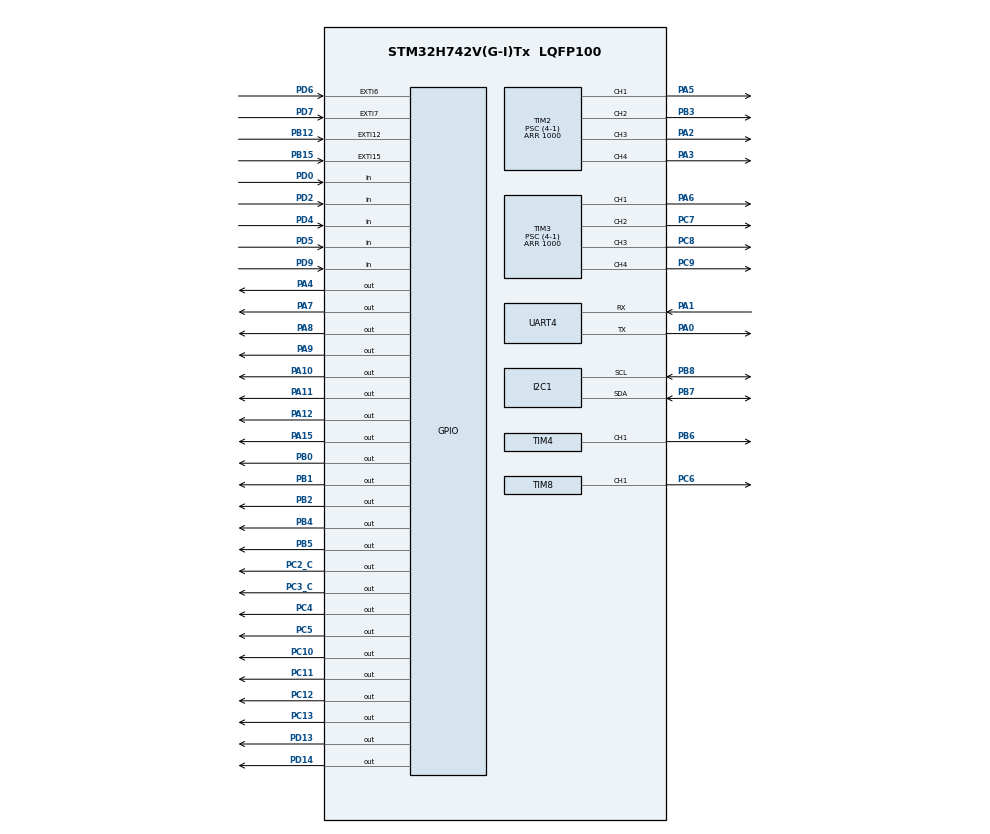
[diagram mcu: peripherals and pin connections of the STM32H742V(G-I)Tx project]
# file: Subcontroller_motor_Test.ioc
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I2C1.Timing=0x109093DC
Mcu.Family=STM32H7
Mcu.Name=STM32H742V(G-I)Tx
Mcu.Package=LQFP100
NVIC.EXTI15_10_IRQn=true\:0\:0\:false\:false\:true\:true\:true\:true
NVIC.EXTI9_5_IRQn=true\:0\:0\:false\:false\:true\:true\:true\:true
NVIC.PriorityGroup=NVIC_PRIORITYGROUP_4
NVIC.TIM2_IRQn=true\:0\:0\:false\:false\:true\:true\:true\:true
NVIC.TIM3_IRQn=true\:0\:0\:false\:false\:true\:true\:true\:true
NVIC.TIM4_IRQn=true\:0\:0\:false\:false\:true\:true\:true\:true
NVIC.TIM7_IRQn=true\:0\:0\:false\:false\:true\:true\:true\:true
NVIC.TIM8_BRK_TIM12_IRQn=true\:0\:0\:false\:false\:true\:true\:true\:true
NVIC.TIM8_CC_IRQn=true\:0\:0\:false\:false\:true\:true\:true\:true
NVIC.TIM8_TRG_COM_TIM14_IRQn=true\:0\:0\:false\:false\:true\:true\:true\:true
NVIC.TIM8_UP_TIM13_IRQn=true\:0\:0\:false\:false\:true\:true\:true\:true
NVIC.UART4_IRQn=true\:0\:0\:false\:false\:true\:true\:true\:true
PA0.Mode=Asynchronous
PA0.Signal=UART4_TX
PA1.Mode=Asynchronous
PA1.Signal=UART4_RX
PA10.PinState=GPIO_PIN_SET
PA10.Signal=GPIO_Output
PA11.PinState=GPIO_PIN_SET
PA11.Signal=GPIO_Output
PA12.PinState=GPIO_PIN_SET
PA12.Signal=GPIO_Output
PA15\ (JTDI).PinState=GPIO_PIN_SET
PA15\ (JTDI).Signal=GPIO_Output
PA2.Signal=S_TIM2_CH3
PA3.Signal=S_TIM2_CH4
PA4.PinState=GPIO_PIN_RESET
PA4.Signal=GPIO_Output
PA5.Signal=S_TIM2_CH1_ETR
PA6.Signal=S_TIM3_CH1
PA7.PinState=GPIO_PIN_RESET
PA7.Signal=GPIO_Output
PA8.PinState=GPIO_PIN_RESET
PA8.Signal=GPIO_Output
PA9.PinState=GPIO_PIN_SET
PA9.Signal=GPIO_Output
PB0.Signal=GPIO_Output
PB1.PinState=GPIO_PIN_SET
PB1.Signal=GPIO_Output
PB12.GPIO_ModeDefaultEXTI=GPIO_MODE_IT_FALLING
PB12.Signal=GPXTI12
PB15.Signal=GPXTI15
PB2.PinState=GPIO_PIN_SET
PB2.Signal=GPIO_Output
PB3\ (JTDO/TRACESWO).Signal=S_TIM2_CH2
PB4\ (NJTRST).PinState=GPIO_PIN_RESET
PB4\ (NJTRST).Signal=GPIO_Output
PB5.PinState=GPIO_PIN_SET
PB5.Signal=GPIO_Output
PB6.Signal=S_TIM4_CH1
PB7.Mode=I2C
PB7.Signal=I2C1_SDA
PB8.Mode=I2C
PB8.Signal=I2C1_SCL
PC10.PinState=GPIO_PIN_RESET
PC10.Signal=GPIO_Output
PC11.PinState=GPIO_PIN_SET
PC11.Signal=GPIO_Output
PC12.PinState=GPIO_PIN_RESET
PC12.Signal=GPIO_Output
PC13.PinState=GPIO_PIN_SET
PC13.Signal=GPIO_Output
PC2_C.PinState=GPIO_PIN_SET
PC2_C.Signal=GPIO_Output
PC3_C.PinState=GPIO_PIN_RESET
PC3_C.Signal=GPIO_Output
PC4.PinState=GPIO_PIN_SET
PC4.Signal=GPIO_Output
PC5.PinState=GPIO_PIN_SET
PC5.Signal=GPIO_Output
PC6.Signal=S_TIM8_CH1
PC7.Signal=S_TIM3_CH2
PC8.Signal=S_TIM3_CH3
PC9.Signal=S_TIM3_CH4
PD0.Signal=GPIO_Input
PD13.PinState=GPIO_PIN_RESET
PD13.Signal=GPIO_Output
PD14.PinState=GPIO_PIN_RESET
PD14.Signal=GPIO_Output
PD2.Signal=GPIO_Input
PD4.Signal=GPIO_Input
PD5.Signal=GPIO_Input
PD6.GPIO_ModeDefaultEXTI=GPIO_MODE_IT_FALLING
PD6.Signal=GPXTI6
PD7.GPIO_ModeDefaultEXTI=GPIO_MODE_IT_FALLING
PD7.Signal=GPXTI7
PD9.Signal=GPIO_Input
ProjectManager.HeapSize=0x200
ProjectManager.StackSize=0x400
ProjectManager.TargetToolchain=STM32CubeIDE
RCC.ADCFreq_Value=129000000
RCC.APB1Freq_Value=75000000
RCC.APB2Freq_Value=75000000
RCC.APB3Freq_Value=75000000
RCC.APB4Freq_Value=75000000
RCC.CortexFreq_Value=300000000
RCC.D1PPRE=RCC_APB3_DIV2
RCC.D2PPRE1=RCC_APB1_DIV2
RCC.D2PPRE2=RCC_APB2_DIV2
RCC.D3PPRE=RCC_APB4_DIV2
RCC.DIVM1=8
RCC.DIVN1=75
RCC.HCLKFreq_Value=150000000
RCC.HPRE=RCC_HCLK_DIV2
RCC.PLL1_VCI_Range-AdvancedSettings=RCC_PLL1VCIRANGE_0
RCC.PLL1_VCO_SEL-AdvancedSettings=RCC_PLL1VCOMEDIUM
RCC.PLL2_VCI_Range-AdvancedSettings=RCC_PLL2VCIRANGE_0
RCC.PLL2_VCO_SEL-AdvancedSettings=RCC_PLL2VCOWIDE
RCC.SYSCLKFreq_VALUE=300000000
RCC.SYSCLKSource=RCC_SYSCLKSOURCE_PLLCLK
RCC.USBFreq_Value=300000000
SH.S_TIM2_CH1_ETR.0=TIM2_CH1,PWM Generation1 CH1
SH.S_TIM2_CH2.0=TIM2_CH2,PWM Generation2 CH2
SH.S_TIM2_CH3.0=TIM2_CH3,PWM Generation3 CH3
SH.S_TIM2_CH4.0=TIM2_CH4,PWM Generation4 CH4
SH.S_TIM3_CH1.0=TIM3_CH1,PWM Generation1 CH1
SH.S_TIM3_CH2.0=TIM3_CH2,PWM Generation2 CH2
SH.S_TIM3_CH3.0=TIM3_CH3,PWM Generation3 CH3
SH.S_TIM3_CH4.0=TIM3_CH4,PWM Generation4 CH4
SH.S_TIM4_CH1.0=TIM4_CH1,PWM Generation1 CH1
SH.S_TIM8_CH1.0=TIM8_CH1,PWM Generation1 CH1
TIM2.Channel-PWM\ Generation1\ CH1=TIM_CHANNEL_1
TIM2.Channel-PWM\ Generation2\ CH2=TIM_CHANNEL_2
TIM2.Channel-PWM\ Generation3\ CH3=TIM_CHANNEL_3
TIM2.Channel-PWM\ Generation4\ CH4=TIM_CHANNEL_4
TIM2.Period=1000
TIM2.Prescaler=(4-1)
TIM2.Pulse-PWM\ Generation1\ CH1=500
TIM2.Pulse-PWM\ Generation2\ CH2=500
TIM2.Pulse-PWM\ Generation3\ CH3=500
TIM2.Pulse-PWM\ Generation4\ CH4=500
TIM3.Channel-PWM\ Generation1\ CH1=TIM_CHANNEL_1
TIM3.Channel-PWM\ Generation2\ CH2=TIM_CHANNEL_2
TIM3.Channel-PWM\ Generation3\ CH3=TIM_CHANNEL_3
TIM3.Channel-PWM\ Generation4\ CH4=TIM_CHANNEL_4
TIM3.Period=1000
TIM3.Prescaler=(4-1)
TIM3.Pulse-PWM\ Generation1\ CH1=500
TIM3.Pulse-PWM\ Generation2\ CH2=500
TIM3.Pulse-PWM\ Generation3\ CH3=500
TIM3.Pulse-PWM\ Generation4\ CH4=500
TIM4.Channel-PWM\ Generation1\ CH1=TIM_CHANNEL_1
TIM4.Period=650
TIM4.Prescaler=(4-1)
TIM4.Pulse-PWM\ Generation1\ CH1=325
TIM7.Period=50000
TIM7.Prescaler=3000
TIM8.Channel-PWM\ Generation1\ CH1=TIM_CHANNEL_1
TIM8.Period=1000
TIM8.Prescaler=(4-1)
TIM8.Pulse-PWM\ Generation1\ CH1=500
VP_TIM2_VS_ClockSourceINT.Mode=Internal
VP_TIM3_VS_ClockSourceINT.Mode=Internal
VP_TIM4_VS_ClockSourceINT.Mode=Internal
VP_TIM7_VS_ClockSourceINT.Mode=Enable_Timer
VP_TIM8_VS_ClockSourceINT.Mode=Internal
board=custom

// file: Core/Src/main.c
/* USER CODE BEGIN Header */
/**
  ******************************************************************************
  * @file           : main.c
  * @brief          : Main program body
  ******************************************************************************
  * @attention
  *
  * Copyright (c) 2022 STMicroelectronics.
  * All rights reserved.
  *
  * This software is licensed under terms that can be found in the LICENSE file
  * in the root directory of this software component.
  * If no LICENSE file comes with this software, it is provided AS-IS.
  *
  ******************************************************************************
  */
/* USER CODE END Header */
#include "main.h"

/* USER CODE BEGIN Includes */
#include <string.h>
#include "../Phoropter/Inc/common.h"

/* USER CODE END Includes */

/* USER CODE BEGIN PD */

private_var pv;

void  Initial_Homing();

/* USER CODE END PD */

I2C_HandleTypeDef hi2c1;
I2C_HandleTypeDef hi2c1;

TIM_HandleTypeDef htim2;
TIM_HandleTypeDef htim3;
TIM_HandleTypeDef htim4;
TIM_HandleTypeDef htim7;
TIM_HandleTypeDef htim8;

UART_HandleTypeDef huart4;

void SystemClock_Config(void);
static void MX_GPIO_Init(void);
static void MX_TIM3_Init(void);
static void MX_TIM8_Init(void);
static void MX_UART4_Init(void);
static void MX_TIM2_Init(void);
static void MX_TIM7_Init(void);
static void MX_TIM4_Init(void);
static void MX_I2C1_Init(void);

/* USER CODE BEGIN 0 */
uint32_t zCmdRx = 0;
/* USER CODE END 0 */

int main(void)
{
	/* USER CODE BEGIN 1 */
	uint32_t flash_magic_num;
	/* USER CODE END 1 */

	/* MCU Configuration--------------------------------------------------------*/

	/* Reset of all peripherals, Initializes the Flash interface and the Systick. */
	HAL_Init();

	/* Configure the system clock */
	SystemClock_Config();

	/* USER CODE BEGIN SysInit */
	/* Initialize the Private variable */
	Init_PV();

	/* USER CODE END SysInit */

	/* Initialize all configured peripherals */
	MX_GPIO_Init();
	MX_TIM3_Init();
	MX_TIM8_Init();
	MX_UART4_Init();
	MX_TIM2_Init();
	MX_TIM7_Init();
	MX_TIM4_Init();
	MX_I2C1_Init();

#if 1

	/* Read the value from the Flash Memory */
	memset(&pv.cal_disc[0], 0x00, sizeof(pv.cal_disc));
	Flash_Read_Data(FLASH_CONF_ADDR, (uint32_t *)&pv.cal_disc[0], 128/4);

	/* Check for the Magic number */
	flash_magic_num = pv.cal_disc[11];

	if (FLASH_MAGIC_NUMBER != flash_magic_num)
	{
		/* USER CODE BEGIN 2 */
		/* Write default calibration data into flash */
		pv.cal_disc[0]  =  2000;
		pv.cal_disc[1]  =  2000;
		pv.cal_disc[2]  =  2000;
		pv.cal_disc[3]  =  2000;
		pv.cal_disc[4]  =  2000;
		pv.cal_disc[5]  =  2000;
		pv.cal_disc[6]  =  0;
		pv.cal_disc[7]  =  180000;
		pv.cal_disc[8]  =  90;
		pv.cal_disc[9]  =  90;
		pv.cal_disc[10] =  0;
		pv.cal_disc[11] =  0x12345678;		//This Value for Left Side Flash Memory

		/* Write the data into the Flash config location */
		Flash_Write_Data(FLASH_CONF_ADDR, (uint32_t *)&pv.cal_disc[0], 128/4);
		HAL_Delay(100);
	}

#endif

	memset(&pv.cal_disc[0], 0x00, sizeof(pv.cal_disc));
	Flash_Read_Data(FLASH_CONF_ADDR, (uint32_t *)&pv.cal_disc[0], 128/4);

	/* enable update interrupt for timer */
	TIM3->DIER |=(1<<0);    //Disc 4 (TIM3_CH1) //Axis (TIM3_CH3)
	TIM8->DIER |=(1<<0);    //DISC 6 (TIM8_CH1)
	TIM4->DIER |=(1<<0);    //PD Motor
	TIM2->DIER |=(1<<0);    //Disc 5 (TIM2_CH2) //Disc 3 (TIM2_CH1) //Disc 1 (TIM2_CH3)
	//Disc 2 (TIM2_CH4)

	/* Trying to read the IO Expander Register */
	/*
	 * Homing position for Disc1 to Disc6, PD motor, DC motor
	 * Prism1 & Prism2 and Axis motor.
	 */

	//Init_IOExpander(&hi2c1);

	/* Set the Homing Position */
	Initial_Homing();

	pv.motor_error = MOTOR_SUCCESS;
	pv.hi2c1   = &hi2c1;

	/* Initialize the UART */
	/* Enable the interrupt for receiving the data from Main board module */
	memset(&pv.rx_buf[0], 0x00, sizeof(pv.rx_buf));
	HAL_UART_RegisterCallback(pv.huart4, HAL_UART_RX_COMPLETE_CB_ID, HAL_UART4_RxCpltCallback);
	HAL_UART_Receive_IT(pv.huart4,&pv.rx_buf[0],sizeof(pv.rx_buf));

	/* USER CODE END 2 */
	/* Infinite loop */
	/* USER CODE BEGIN WHILE */
	while(1)
	{
		/* Check the motor status and Send the status to the Main board */
		check_motor_status();

    	/* Call the Receive function */
    	MBCmdReceivefunc();

    	/* USER CODE END WHILE */

	}
}

void SystemClock_Config(void)
{
	RCC_OscInitTypeDef RCC_OscInitStruct = {0};
	RCC_ClkInitTypeDef RCC_ClkInitStruct = {0};

	/** Supply configuration update enable
	 */
	HAL_PWREx_ConfigSupply(PWR_LDO_SUPPLY);

	/** Configure the main internal regulator output voltage
	 */
	__HAL_PWR_VOLTAGESCALING_CONFIG(PWR_REGULATOR_VOLTAGE_SCALE2);

	while(!__HAL_PWR_GET_FLAG(PWR_FLAG_VOSRDY)) {}

	/** Initializes the RCC Oscillators according to the specified parameters
	 * in the RCC_OscInitTypeDef structure.
	 */
	RCC_OscInitStruct.OscillatorType = RCC_OSCILLATORTYPE_HSI;
	RCC_OscInitStruct.HSIState = RCC_HSI_DIV1;
	RCC_OscInitStruct.HSICalibrationValue = RCC_HSICALIBRATION_DEFAULT;
	RCC_OscInitStruct.PLL.PLLState = RCC_PLL_ON;
	RCC_OscInitStruct.PLL.PLLSource = RCC_PLLSOURCE_HSI;
	RCC_OscInitStruct.PLL.PLLM = 8;
	RCC_OscInitStruct.PLL.PLLN = 75;
	RCC_OscInitStruct.PLL.PLLP = 2;
	RCC_OscInitStruct.PLL.PLLQ = 2;
	RCC_OscInitStruct.PLL.PLLR = 2;
	RCC_OscInitStruct.PLL.PLLRGE = RCC_PLL1VCIRANGE_3;
	RCC_OscInitStruct.PLL.PLLVCOSEL = RCC_PLL1VCOWIDE;
	RCC_OscInitStruct.PLL.PLLFRACN = 0;
	if (HAL_RCC_OscConfig(&RCC_OscInitStruct) != HAL_OK)
	{
		Error_Handler();
	}

	/** Initializes the CPU, AHB and APB buses clocks
	 */
	RCC_ClkInitStruct.ClockType = RCC_CLOCKTYPE_HCLK|RCC_CLOCKTYPE_SYSCLK
                              |RCC_CLOCKTYPE_PCLK1|RCC_CLOCKTYPE_PCLK2
                              |RCC_CLOCKTYPE_D3PCLK1|RCC_CLOCKTYPE_D1PCLK1;
	RCC_ClkInitStruct.SYSCLKSource = RCC_SYSCLKSOURCE_PLLCLK;
	RCC_ClkInitStruct.SYSCLKDivider = RCC_SYSCLK_DIV1;
	RCC_ClkInitStruct.AHBCLKDivider = RCC_HCLK_DIV2;
	RCC_ClkInitStruct.APB3CLKDivider = RCC_APB3_DIV2;
	RCC_ClkInitStruct.APB1CLKDivider = RCC_APB1_DIV2;
	RCC_ClkInitStruct.APB2CLKDivider = RCC_APB2_DIV2;
	RCC_ClkInitStruct.APB4CLKDivider = RCC_APB4_DIV2;

	if (HAL_RCC_ClockConfig(&RCC_ClkInitStruct, FLASH_LATENCY_2) != HAL_OK)
	{
		Error_Handler();
	}
}

	/**
	 * @brief I2C1 Initialization Function
	 * @param None
	 * @retval None
	 */
static void MX_I2C1_Init(void)
{

	hi2c1.Instance = I2C1;
	hi2c1.Init.Timing = 0x109093DC;
	hi2c1.Init.OwnAddress1 = 0;
	hi2c1.Init.AddressingMode = I2C_ADDRESSINGMODE_7BIT;
	hi2c1.Init.DualAddressMode = I2C_DUALADDRESS_DISABLE;
	hi2c1.Init.OwnAddress2 = 0;
	hi2c1.Init.OwnAddress2Masks = I2C_OA2_NOMASK;
	hi2c1.Init.GeneralCallMode = I2C_GENERALCALL_DISABLE;
	hi2c1.Init.NoStretchMode = I2C_NOSTRETCH_DISABLE;
	if (HAL_I2C_Init(&hi2c1) != HAL_OK)
	{
		Error_Handler();
	}

	/** Configure Analogue filter
	 */
	if (HAL_I2CEx_ConfigAnalogFilter(&hi2c1, I2C_ANALOGFILTER_ENABLE) != HAL_OK)
	{
		Error_Handler();
	}

	/** Configure Digital filter
	 */
	if (HAL_I2CEx_ConfigDigitalFilter(&hi2c1, 0) != HAL_OK)
	{
		Error_Handler();
	}

	}

	/**
	 * @brief TIM2 Initialization Function
	 * @param None
	 * @retval None
	 */
static void MX_TIM2_Init(void)
{

	TIM_ClockConfigTypeDef sClockSourceConfig = {0};
	TIM_MasterConfigTypeDef sMasterConfig = {0};
	TIM_OC_InitTypeDef sConfigOC = {0};

	htim2.Instance = TIM2;
	htim2.Init.Prescaler = (4-1);
	htim2.Init.CounterMode = TIM_COUNTERMODE_UP;
	htim2.Init.Period = 1000;
	htim2.Init.ClockDivision = TIM_CLOCKDIVISION_DIV1;
	htim2.Init.AutoReloadPreload = TIM_AUTORELOAD_PRELOAD_DISABLE;
	if (HAL_TIM_Base_Init(&htim2) != HAL_OK)
	{
		Error_Handler();
	}
	sClockSourceConfig.ClockSource = TIM_CLOCKSOURCE_INTERNAL;
	if (HAL_TIM_ConfigClockSource(&htim2, &sClockSourceConfig) != HAL_OK)
	{
		Error_Handler();
	}
	if (HAL_TIM_PWM_Init(&htim2) != HAL_OK)
	{
		Error_Handler();
	}
	sMasterConfig.MasterOutputTrigger = TIM_TRGO_RESET;
	sMasterConfig.MasterSlaveMode = TIM_MASTERSLAVEMODE_DISABLE;
	if (HAL_TIMEx_MasterConfigSynchronization(&htim2, &sMasterConfig) != HAL_OK)
	{
		Error_Handler();
	}
	sConfigOC.OCMode = TIM_OCMODE_PWM1;
	sConfigOC.Pulse = 500;
	sConfigOC.OCPolarity = TIM_OCPOLARITY_HIGH;
	sConfigOC.OCFastMode = TIM_OCFAST_DISABLE;
	if (HAL_TIM_PWM_ConfigChannel(&htim2, &sConfigOC, TIM_CHANNEL_1) != HAL_OK)
	{
		Error_Handler();
	}
	if (HAL_TIM_PWM_ConfigChannel(&htim2, &sConfigOC, TIM_CHANNEL_2) != HAL_OK)
	{
		Error_Handler();
	}
	if (HAL_TIM_PWM_ConfigChannel(&htim2, &sConfigOC, TIM_CHANNEL_3) != HAL_OK)
	{
		Error_Handler();
	}
	if (HAL_TIM_PWM_ConfigChannel(&htim2, &sConfigOC, TIM_CHANNEL_4) != HAL_OK)
	{
		Error_Handler();
	}
	HAL_TIM_MspPostInit(&htim2);

}

static void MX_TIM3_Init(void)
{

	TIM_ClockConfigTypeDef sClockSourceConfig = {0};
	TIM_MasterConfigTypeDef sMasterConfig = {0};
	TIM_OC_InitTypeDef sConfigOC = {0};

	htim3.Instance = TIM3;
	htim3.Init.Prescaler = (4-1);
	htim3.Init.CounterMode = TIM_COUNTERMODE_UP;
	htim3.Init.Period = 1000;
	htim3.Init.ClockDivision = TIM_CLOCKDIVISION_DIV1;
	htim3.Init.AutoReloadPreload = TIM_AUTORELOAD_PRELOAD_DISABLE;
	if (HAL_TIM_Base_Init(&htim3) != HAL_OK)
	{
		Error_Handler();
	}
	sClockSourceConfig.ClockSource = TIM_CLOCKSOURCE_INTERNAL;
	if (HAL_TIM_ConfigClockSource(&htim3, &sClockSourceConfig) != HAL_OK)
	{
		Error_Handler();
	}
	if (HAL_TIM_PWM_Init(&htim3) != HAL_OK)
	{
		Error_Handler();
	}
	sMasterConfig.MasterOutputTrigger = TIM_TRGO_RESET;
	sMasterConfig.MasterSlaveMode = TIM_MASTERSLAVEMODE_DISABLE;
	if (HAL_TIMEx_MasterConfigSynchronization(&htim3, &sMasterConfig) != HAL_OK)
	{
		Error_Handler();
	}
	sConfigOC.OCMode = TIM_OCMODE_PWM1;
	sConfigOC.Pulse = 500;
	sConfigOC.OCPolarity = TIM_OCPOLARITY_HIGH;
	sConfigOC.OCFastMode = TIM_OCFAST_DISABLE;
	if (HAL_TIM_PWM_ConfigChannel(&htim3, &sConfigOC, TIM_CHANNEL_1) != HAL_OK)
	{
		Error_Handler();
	}
	if (HAL_TIM_PWM_ConfigChannel(&htim3, &sConfigOC, TIM_CHANNEL_2) != HAL_OK)
	{
		Error_Handler();
	}
	if (HAL_TIM_PWM_ConfigChannel(&htim3, &sConfigOC, TIM_CHANNEL_3) != HAL_OK)
	{
		Error_Handler();
	}
	if (HAL_TIM_PWM_ConfigChannel(&htim3, &sConfigOC, TIM_CHANNEL_4) != HAL_OK)
	{
		Error_Handler();
	}
	HAL_TIM_MspPostInit(&htim3);

}

static void MX_TIM4_Init(void)
{

	TIM_ClockConfigTypeDef sClockSourceConfig = {0};
	TIM_MasterConfigTypeDef sMasterConfig = {0};
	TIM_OC_InitTypeDef sConfigOC = {0};

	htim4.Instance = TIM4;
	htim4.Init.Prescaler = (4-1);
	htim4.Init.CounterMode = TIM_COUNTERMODE_UP;
	htim4.Init.Period = 650;
	htim4.Init.ClockDivision = TIM_CLOCKDIVISION_DIV1;
	htim4.Init.AutoReloadPreload = TIM_AUTORELOAD_PRELOAD_DISABLE;
	if (HAL_TIM_Base_Init(&htim4) != HAL_OK)
	{
		Error_Handler();
	}
	sClockSourceConfig.ClockSource = TIM_CLOCKSOURCE_INTERNAL;
	if (HAL_TIM_ConfigClockSource(&htim4, &sClockSourceConfig) != HAL_OK)
	{
		Error_Handler();
	}
	if (HAL_TIM_PWM_Init(&htim4) != HAL_OK)
	{
		Error_Handler();
	}
	sMasterConfig.MasterOutputTrigger = TIM_TRGO_RESET;
	sMasterConfig.MasterSlaveMode = TIM_MASTERSLAVEMODE_DISABLE;
	if (HAL_TIMEx_MasterConfigSynchronization(&htim4, &sMasterConfig) != HAL_OK)
	{
		Error_Handler();
	}
	sConfigOC.OCMode = TIM_OCMODE_PWM1;
	sConfigOC.Pulse = 325;
	sConfigOC.OCPolarity = TIM_OCPOLARITY_HIGH;
	sConfigOC.OCFastMode = TIM_OCFAST_DISABLE;
	if (HAL_TIM_PWM_ConfigChannel(&htim4, &sConfigOC, TIM_CHANNEL_1) != HAL_OK)
	{
		Error_Handler();
	}
	HAL_TIM_MspPostInit(&htim4);

}

static void MX_TIM7_Init(void)
{

	TIM_MasterConfigTypeDef sMasterConfig = {0};

	htim7.Instance = TIM7;
	htim7.Init.Prescaler = 3000;
	htim7.Init.CounterMode = TIM_COUNTERMODE_UP;
	htim7.Init.Period = 50000;
	htim7.Init.AutoReloadPreload = TIM_AUTORELOAD_PRELOAD_DISABLE;
	if (HAL_TIM_Base_Init(&htim7) != HAL_OK)
	{
		Error_Handler();
	}
	sMasterConfig.MasterOutputTrigger = TIM_TRGO_RESET;
	sMasterConfig.MasterSlaveMode = TIM_MASTERSLAVEMODE_DISABLE;
	if (HAL_TIMEx_MasterConfigSynchronization(&htim7, &sMasterConfig) != HAL_OK)
	{
		Error_Handler();
	}

}

static void MX_TIM8_Init(void)
{

	TIM_ClockConfigTypeDef sClockSourceConfig = {0};
	TIM_MasterConfigTypeDef sMasterConfig = {0};
	TIM_OC_InitTypeDef sConfigOC = {0};
	TIM_BreakDeadTimeConfigTypeDef sBreakDeadTimeConfig = {0};

	htim8.Instance = TIM8;
	htim8.Init.Prescaler = (4-1);
	htim8.Init.CounterMode = TIM_COUNTERMODE_UP;
	htim8.Init.Period = 1000;
	htim8.Init.ClockDivision = TIM_CLOCKDIVISION_DIV1;
	htim8.Init.RepetitionCounter = 0;
	htim8.Init.AutoReloadPreload = TIM_AUTORELOAD_PRELOAD_DISABLE;
	if (HAL_TIM_Base_Init(&htim8) != HAL_OK)
	{
		Error_Handler();
	}
	sClockSourceConfig.ClockSource = TIM_CLOCKSOURCE_INTERNAL;
	if (HAL_TIM_ConfigClockSource(&htim8, &sClockSourceConfig) != HAL_OK)
	{
		Error_Handler();
	}
	if (HAL_TIM_PWM_Init(&htim8) != HAL_OK)
	{
		Error_Handler();
	}
	sMasterConfig.MasterOutputTrigger = TIM_TRGO_RESET;
	sMasterConfig.MasterOutputTrigger2 = TIM_TRGO2_RESET;
	sMasterConfig.MasterSlaveMode = TIM_MASTERSLAVEMODE_DISABLE;
	if (HAL_TIMEx_MasterConfigSynchronization(&htim8, &sMasterConfig) != HAL_OK)
	{
		Error_Handler();
	}
	sConfigOC.OCMode = TIM_OCMODE_PWM1;
	sConfigOC.Pulse = 500;
	sConfigOC.OCPolarity = TIM_OCPOLARITY_HIGH;
	sConfigOC.OCNPolarity = TIM_OCNPOLARITY_HIGH;
	sConfigOC.OCFastMode = TIM_OCFAST_DISABLE;
	sConfigOC.OCIdleState = TIM_OCIDLESTATE_RESET;
	sConfigOC.OCNIdleState = TIM_OCNIDLESTATE_RESET;
	if (HAL_TIM_PWM_ConfigChannel(&htim8, &sConfigOC, TIM_CHANNEL_1) != HAL_OK)
	{
		Error_Handler();
	}
	sBreakDeadTimeConfig.OffStateRunMode = TIM_OSSR_DISABLE;
	sBreakDeadTimeConfig.OffStateIDLEMode = TIM_OSSI_DISABLE;
	sBreakDeadTimeConfig.LockLevel = TIM_LOCKLEVEL_OFF;
	sBreakDeadTimeConfig.DeadTime = 0;
	sBreakDeadTimeConfig.BreakState = TIM_BREAK_DISABLE;
	sBreakDeadTimeConfig.BreakPolarity = TIM_BREAKPOLARITY_HIGH;
	sBreakDeadTimeConfig.BreakFilter = 0;
	sBreakDeadTimeConfig.Break2State = TIM_BREAK2_DISABLE;
	sBreakDeadTimeConfig.Break2Polarity = TIM_BREAK2POLARITY_HIGH;
	sBreakDeadTimeConfig.Break2Filter = 0;
	sBreakDeadTimeConfig.AutomaticOutput = TIM_AUTOMATICOUTPUT_DISABLE;
	if (HAL_TIMEx_ConfigBreakDeadTime(&htim8, &sBreakDeadTimeConfig) != HAL_OK)
	{
		Error_Handler();
	}
	HAL_TIM_MspPostInit(&htim8);

}

static void MX_UART4_Init(void)
{

	huart4.Instance = UART4;
	huart4.Init.BaudRate = 115200;
	huart4.Init.WordLength = UART_WORDLENGTH_8B;
	huart4.Init.StopBits = UART_STOPBITS_1;
	huart4.Init.Parity = UART_PARITY_NONE;
	huart4.Init.Mode = UART_MODE_TX_RX;
	huart4.Init.HwFlowCtl = UART_HWCONTROL_NONE;
	huart4.Init.OverSampling = UART_OVERSAMPLING_16;
	huart4.Init.OneBitSampling = UART_ONE_BIT_SAMPLE_DISABLE;
	huart4.Init.ClockPrescaler = UART_PRESCALER_DIV1;
	huart4.AdvancedInit.AdvFeatureInit = UART_ADVFEATURE_NO_INIT;
	if (HAL_UART_Init(&huart4) != HAL_OK)
	{
		Error_Handler();
	}
	if (HAL_UARTEx_SetTxFifoThreshold(&huart4, UART_TXFIFO_THRESHOLD_1_8) != HAL_OK)
	{
		Error_Handler();
	}
	if (HAL_UARTEx_SetRxFifoThreshold(&huart4, UART_RXFIFO_THRESHOLD_1_8) != HAL_OK)
	{
		Error_Handler();
	}
	if (HAL_UARTEx_DisableFifoMode(&huart4) != HAL_OK)
	{
		Error_Handler();
	}

}

static void MX_GPIO_Init(void)
{
	GPIO_InitTypeDef GPIO_InitStruct = {0};

	/* GPIO Ports Clock Enable */
	__HAL_RCC_GPIOC_CLK_ENABLE();
	__HAL_RCC_GPIOA_CLK_ENABLE();
	__HAL_RCC_GPIOB_CLK_ENABLE();
	__HAL_RCC_GPIOD_CLK_ENABLE();

	/*Configure GPIO pin Output Level */
	HAL_GPIO_WritePin(GPIOC, GPIO_PIN_13|GPIO_PIN_2|GPIO_PIN_4|GPIO_PIN_5
				|GPIO_PIN_11, GPIO_PIN_SET);

	/*Configure GPIO pin Output Level */
	HAL_GPIO_WritePin(GPIOC, GPIO_PIN_3|GPIO_PIN_10|GPIO_PIN_12, GPIO_PIN_RESET);

	/*Configure GPIO pin Output Level */
	HAL_GPIO_WritePin(GPIOA, GPIO_PIN_4|GPIO_PIN_7|GPIO_PIN_8, GPIO_PIN_RESET);

	/*Configure GPIO pin Output Level */
	HAL_GPIO_WritePin(GPIOB, GPIO_PIN_0|GPIO_PIN_4, GPIO_PIN_RESET);

	/*Configure GPIO pin Output Level */
	HAL_GPIO_WritePin(GPIOB, GPIO_PIN_1|GPIO_PIN_2|GPIO_PIN_5, GPIO_PIN_SET);

	/*Configure GPIO pin Output Level */
	HAL_GPIO_WritePin(GPIOD, GPIO_PIN_13|GPIO_PIN_14, GPIO_PIN_RESET);

	/*Configure GPIO pin Output Level */
	HAL_GPIO_WritePin(GPIOA, GPIO_PIN_9|GPIO_PIN_10|GPIO_PIN_11|GPIO_PIN_12
			|GPIO_PIN_15, GPIO_PIN_SET);

	/*Configure GPIO pins : PC13 PC2 PC3 PC4
							   PC5 PC10 PC11 PC12 */
	GPIO_InitStruct.Pin = GPIO_PIN_13|GPIO_PIN_2|GPIO_PIN_3|GPIO_PIN_4
			|GPIO_PIN_5|GPIO_PIN_10|GPIO_PIN_11|GPIO_PIN_12;
	GPIO_InitStruct.Mode = GPIO_MODE_OUTPUT_PP;
	GPIO_InitStruct.Pull = GPIO_NOPULL;
	GPIO_InitStruct.Speed = GPIO_SPEED_FREQ_LOW;
	HAL_GPIO_Init(GPIOC, &GPIO_InitStruct);

	/*Configure GPIO pins : PA4 PA7 PA8 PA9
							   PA10 PA11 PA12 PA15 */
	GPIO_InitStruct.Pin = GPIO_PIN_4|GPIO_PIN_7|GPIO_PIN_8|GPIO_PIN_9
			|GPIO_PIN_10|GPIO_PIN_11|GPIO_PIN_12|GPIO_PIN_15;
	GPIO_InitStruct.Mode = GPIO_MODE_OUTPUT_PP;
	GPIO_InitStruct.Pull = GPIO_NOPULL;
	GPIO_InitStruct.Speed = GPIO_SPEED_FREQ_LOW;
	HAL_GPIO_Init(GPIOA, &GPIO_InitStruct);

	/*Configure GPIO pins : PB0 PB1 PB2 PB4
							   PB5 */
	GPIO_InitStruct.Pin = GPIO_PIN_0|GPIO_PIN_1|GPIO_PIN_2|GPIO_PIN_4
			|GPIO_PIN_5;
	GPIO_InitStruct.Mode = GPIO_MODE_OUTPUT_PP;
	GPIO_InitStruct.Pull = GPIO_NOPULL;
	GPIO_InitStruct.Speed = GPIO_SPEED_FREQ_LOW;
	HAL_GPIO_Init(GPIOB, &GPIO_InitStruct);

	/*Configure GPIO pin : PB12 */
	GPIO_InitStruct.Pin = GPIO_PIN_12;
	GPIO_InitStruct.Mode = GPIO_MODE_IT_FALLING;
	GPIO_InitStruct.Pull = GPIO_NOPULL;
	HAL_GPIO_Init(GPIOB, &GPIO_InitStruct);

	/*Configure GPIO pin : PB15 */
	GPIO_InitStruct.Pin = GPIO_PIN_15;
	GPIO_InitStruct.Mode = GPIO_MODE_IT_RISING;
	GPIO_InitStruct.Pull = GPIO_NOPULL;
	HAL_GPIO_Init(GPIOB, &GPIO_InitStruct);

	/*Configure GPIO pins : PD9 PD0 PD2 PD4 PD8 PD10
							   PD5 */
	GPIO_InitStruct.Pin = GPIO_PIN_9|GPIO_PIN_8|GPIO_PIN_10|GPIO_PIN_0|GPIO_PIN_2|GPIO_PIN_4
			|GPIO_PIN_5;
	GPIO_InitStruct.Mode = GPIO_MODE_INPUT;
	GPIO_InitStruct.Pull = GPIO_NOPULL;
	HAL_GPIO_Init(GPIOD, &GPIO_InitStruct);

	/*Configure GPIO pins : PD13 PD14 */
	GPIO_InitStruct.Pin = GPIO_PIN_13|GPIO_PIN_14;
	GPIO_InitStruct.Mode = GPIO_MODE_OUTPUT_PP;
	GPIO_InitStruct.Pull = GPIO_NOPULL;
	GPIO_InitStruct.Speed = GPIO_SPEED_FREQ_LOW;
	HAL_GPIO_Init(GPIOD, &GPIO_InitStruct);

	/*Configure GPIO pins : PD6 PD7 */
	GPIO_InitStruct.Pin = GPIO_PIN_6|GPIO_PIN_7;
	GPIO_InitStruct.Mode = GPIO_MODE_IT_FALLING;
	GPIO_InitStruct.Pull = GPIO_NOPULL;
	HAL_GPIO_Init(GPIOD, &GPIO_InitStruct);

	/* EXTI interrupt init*/
	HAL_NVIC_SetPriority(EXTI9_5_IRQn, 0, 0);
	HAL_NVIC_EnableIRQ(EXTI9_5_IRQn);

	HAL_NVIC_SetPriority(EXTI15_10_IRQn, 0, 0);
	HAL_NVIC_EnableIRQ(EXTI15_10_IRQn);

}

/* USER CODE BEGIN 4 */
/**
 * @brief  Rx Transfer completed callback.
 * @param  huart UART handle.
 * @retval None
 */
void HAL_UART4_RxCpltCallback(UART_HandleTypeDef *huart)
{
	pv.write_ptr = 0;
	HAL_UART_Receive_IT(pv.huart4,&pv.rx_buf[0],sizeof(pv.rx_buf));
}

/**
 * @brief Transmit the ack packet to UART.
 * @param buffer and buffer size.
 * @retval None.
 */
void dump_packet(uint8_t *buf, uint16_t size)
{
	uint16_t index;
	for(index=0; index < size; index++)
	{
		HAL_UART_Transmit_IT(&huart4,&buf[index], 1);
		HAL_Delay(10);
	}
}

/* EXTI Line15 External Interrupt ISR Handler CallBackFun */
void HAL_GPIO_EXTI_Callback(uint16_t GPIO_Pin)
{
	if(GPIO_Pin == GPIO_PIN_12)
	{
		if(pv.pd_flag1 == 1)
		{
			pv.PD_flag = 1;
		}
		if(pv.pd_flag1 == 0)
		{
			pv.PD_flag = 0;
		}
	}
}

/**
 * @brief This function handles EXTI line[9:5] interrupts.
 */
#if 0
void EXTI9_5_IRQHandler(void)
{
	uint32_t pending = EXTI->PR1;

	if(pending & (1 << 6))
	{
		__HAL_GPIO_EXTI_CLEAR_IT(GPIO_PIN_6);
		__HAL_GPIO_EXTI_CLEAR_FLAG(GPIO_PIN_6);
		pv.dc_int2 = 1;
	}

	if(pending & (1 << 7))
	{
		__HAL_GPIO_EXTI_CLEAR_IT(GPIO_PIN_7);
		__HAL_GPIO_EXTI_CLEAR_FLAG(GPIO_PIN_7);
		pv.dc_int1 = 1;
	}

}

#endif
/* USER CODE END 4 */

void Error_Handler(void)
{
	__disable_irq();
	while (1)
	{
	}
}
